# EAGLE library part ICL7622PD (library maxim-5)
OP AMP

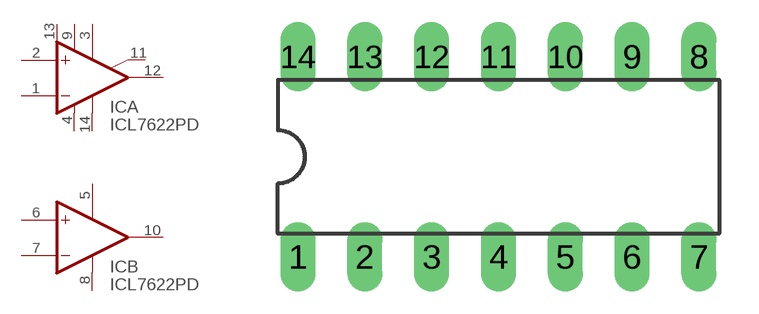
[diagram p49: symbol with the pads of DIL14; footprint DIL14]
Designator prefix IC; gates A=OPOFF+NC P=2V+V- B=OPOFF

## ICL7622PD  [DIL14]
1  A:-IN  in
2  A:+IN  in
3  A:OFF1  pas
4  P:V-  pwr
5  B:OFF1  pas
6  B:+IN  in
7  B:-IN  in
8  B:OFF2  pas
9  P:V+  pwr
10  B:OUT  out
11  A:NC  pas
12  A:OUT  out
13  P:V+  pwr
14  A:OFF2  pas

## Footprint DIL14 (pad centres in mm)
Dual In Line Package
drill 0.813 long: 1 -7.62,-3.81; 2 -5.08,-3.81; 3 -2.54,-3.81; 4 0,-3.81; 5 2.54,-3.81; 6 5.08,-3.81; 7 7.62,-3.81; 8 7.62,3.81; 9 5.08,3.81; 10 2.54,3.81; 11 0,3.81; 12 -2.54,3.81; 13 -5.08,3.81; 14 -7.62,3.81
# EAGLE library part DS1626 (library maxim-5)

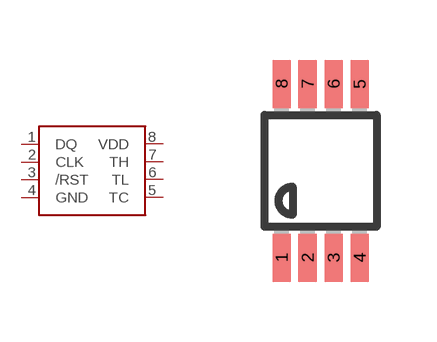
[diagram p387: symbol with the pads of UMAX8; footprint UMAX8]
Designator prefix IC

## DS1626  [UMAX8]
1  DQ
2  CLK
3  /RST
4  GND
5  TC
6  TL
7  TH
8  VDD

## Footprint UMAX8 (pad centres in mm)
micro MAX Package
smd 0.45 x 1.2: 1 -0.975,-2.175; 2 -0.325,-2.175; 3 0.325,-2.175; 4 0.975,-2.175; 5 0.975,2.175; 6 0.325,2.175; 7 -0.325,2.175; 8 -0.975,2.175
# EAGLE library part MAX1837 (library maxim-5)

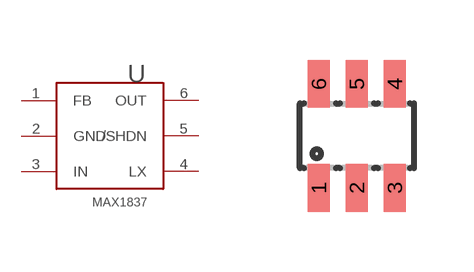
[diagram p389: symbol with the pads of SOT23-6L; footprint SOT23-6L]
Designator prefix -

## MAX1837SOT23  [SOT23-6L]
1  FB  in
2  GND  pwr
3  IN  in
4  LX  out
5  /SHDN  in
6  OUT  out

## Footprint SOT23-6L (pad centres in mm)
Small Outline Transistor
smd 0.55 x 1.2: 1 -0.95,-1.3; 2 0,-1.3; 3 0.95,-1.3; 4 0.95,1.3; 5 0,1.3; 6 -0.95,1.3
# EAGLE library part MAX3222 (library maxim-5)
RS232 TRANSCEIVER

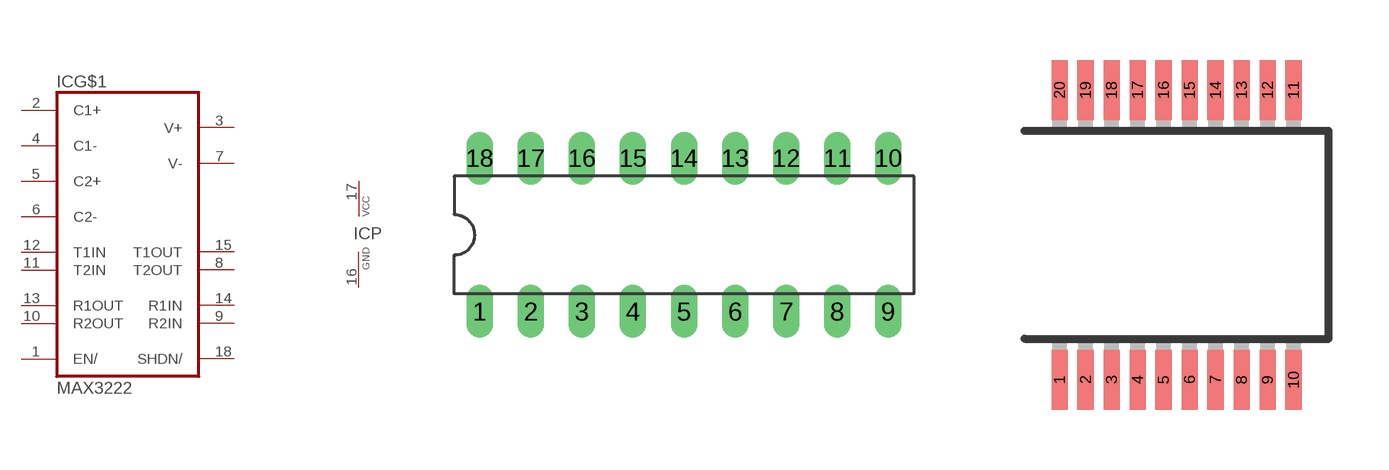
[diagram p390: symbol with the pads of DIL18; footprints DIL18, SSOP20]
Designator prefix IC; gates G$1=MAX3222 P=VCC-GND

## MAX3222CPN  [DIL18]
1  G$1:EN/  in
2  G$1:C1+  pas
3  G$1:V+  pas
4  G$1:C1-  pas
5  G$1:C2+  pas
6  G$1:C2-  pas
7  G$1:V-  pas
8  G$1:T2OUT  out
9  G$1:R2IN  in
10  G$1:R2OUT  out
11  G$1:T2IN  in
12  G$1:T1IN  in
13  G$1:R1OUT  out
14  G$1:R1IN  in
15  G$1:T1OUT  out
16  P:GND  pwr
17  P:VCC  pwr
18  G$1:SHDN/  in

## MAX3222CAP  [SSOP20]
1  G$1:EN/  in
2  G$1:C1+  pas
3  G$1:V+  pas
4  G$1:C1-  pas
5  G$1:C2+  pas
6  G$1:C2-  pas
7  G$1:V-  pas
8  G$1:T2OUT  out
9  G$1:R2IN  in
10  G$1:R2OUT  out
12  G$1:T2IN  in
13  G$1:T1IN  in
15  G$1:R1OUT  out
16  G$1:R1IN  in
17  G$1:T1OUT  out
18  P:GND  pwr
19  P:VCC  pwr
20  G$1:SHDN/  in

## MAX3222CUP  [TSSOP20]
Pads as for SSOP20

## MAX3222CWN  [SO18L]
Pads as for DIL18

## Footprint DIL18 (pad centres in mm)
Dual In Line Package
drill 0.813 long: 1 -10.16,-3.81; 2 -7.62,-3.81; 3 -5.08,-3.81; 4 -2.54,-3.81; 5 0,-3.81; 6 2.54,-3.81; 7 5.08,-3.81; 8 7.62,-3.81; 9 10.16,-3.81; 10 10.16,3.81; 11 7.62,3.81; 12 5.08,3.81; 13 2.54,3.81; 14 0,3.81; 15 -2.54,3.81; 16 -5.08,3.81; 17 -7.62,3.81; 18 -10.16,3.81

## Footprint SSOP20 (pad centres in mm)
Shrink Small Outline Package package type SS
smd 0.4 x 1.5: 1 -2.925,-3.625; 2 -2.275,-3.625; 3 -1.625,-3.625; 4 -0.975,-3.625; 5 -0.325,-3.625; 6 0.325,-3.625; 7 0.975,-3.625; 8 1.625,-3.625; 9 2.275,-3.625; 10 2.925,-3.625; 11 2.925,3.625; 12 2.275,3.625; 13 1.625,3.625; 14 0.975,3.625; 15 0.325,3.625; 16 -0.325,3.625; 17 -0.975,3.625; 18 -1.625,3.625; 19 -2.275,3.625; 20 -2.925,3.625

## Footprint TSSOP20 (pad centres in mm)
Thin Shrink Small Outline Plastic 20 MAX3223-MAX3243.pdf
smd 0.305 x 0.991: 1 -2.925,-2.918; 2 -2.275,-2.918; 3 -1.625,-2.918; 4 -0.975,-2.918; 5 -0.325,-2.918; 6 0.325,-2.918; 7 0.975,-2.918; 8 1.625,-2.918; 9 2.275,-2.918; 10 2.925,-2.918; 11 2.925,2.918; 12 2.275,2.918; 13 1.625,2.918; 14 0.975,2.918; 15 0.325,2.918; 16 -0.325,2.918; 17 -0.975,2.918; 18 -1.625,2.918; 19 -2.275,2.918; 20 -2.925,2.918

## Footprint SO18L (pad centres in mm)
Small Outline Package
smd 0.66 x 2.032: 1 -5.08,-4.902; 2 -3.81,-4.902; 3 -2.54,-4.902; 4 -1.27,-4.902; 5 0,-4.902; 6 1.27,-4.902; 7 2.54,-4.902; 8 3.81,-4.902; 9 5.08,-4.902; 10 5.08,4.902; 11 3.81,4.902; 12 2.54,4.902; 13 1.27,4.902; 14 0,4.902; 15 -1.27,4.902; 16 -2.54,4.902; 17 -3.81,4.902; 18 -5.08,4.902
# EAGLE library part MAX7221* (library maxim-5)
Serially Interfaced, 8-Digit LED Display Drivers

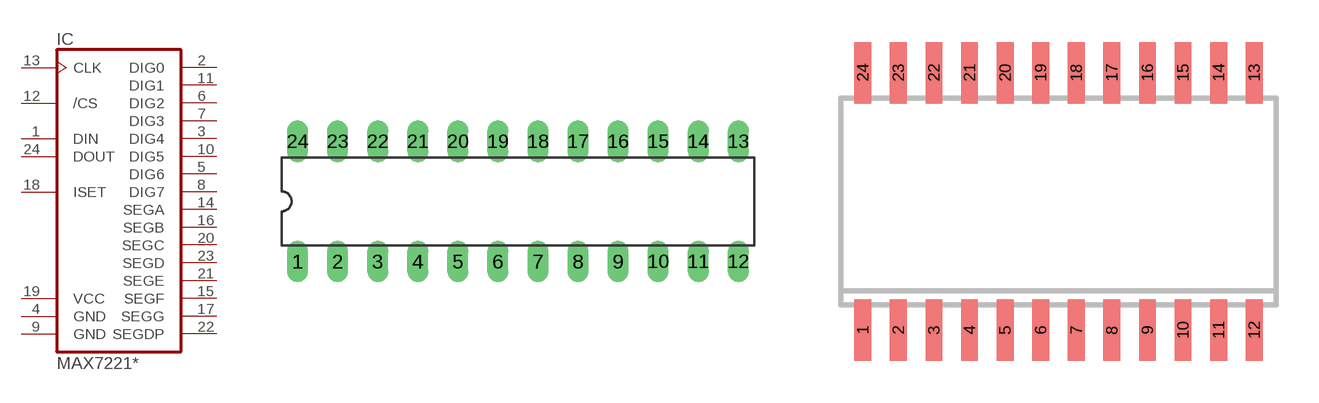
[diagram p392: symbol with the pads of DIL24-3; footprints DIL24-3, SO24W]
Designator prefix IC

## MAX7221CNG, MAX7221ENG  [DIL24-3]
1  DIN  in
2  DIG0  oc
3  DIG4  oc
4  GND  pwr
5  DIG6  oc
6  DIG2  oc
7  DIG3  oc
8  DIG7  oc
9  GND  pwr
10  DIG5  oc
11  DIG1  oc
12  /CS  in
13  CLK  in
14  SEGA  out
15  SEGF  out
16  SEGB  out
17  SEGG  out
18  ISET  in
19  VCC  pwr
20  SEGC  out
21  SEGE  out
22  SEGDP  out
23  SEGD  out
24  DOUT  out

## MAX7221CWG, MAX7221EWG  [SO24W]
Pads as for DIL24-3

## Footprint DIL24-3 (pad centres in mm)
Dual In Line Package 0.3 inch
drill 0.813 long: 1 -13.97,-3.81; 2 -11.43,-3.81; 3 -8.89,-3.81; 4 -6.35,-3.81; 5 -3.81,-3.81; 6 -1.27,-3.81; 7 1.27,-3.81; 8 3.81,-3.81; 9 6.35,-3.81; 10 8.89,-3.81; 11 11.43,-3.81; 12 13.97,-3.81; 13 13.97,3.81; 14 11.43,3.81; 15 8.89,3.81; 16 6.35,3.81; 17 3.81,3.81; 18 1.27,3.81; 19 -1.27,3.81; 20 -3.81,3.81; 21 -6.35,3.81; 22 -8.89,3.81; 23 -11.43,3.81; 24 -13.97,3.81

## Footprint SO24W (pad centres in mm)
SMALL OUTLINE INTEGRATED CIRCUIT wide body 7.5 mm/JEDEC MO-119AA
smd 0.6 x 2.2: 1 -6.985,-4.6; 2 -5.715,-4.6; 3 -4.445,-4.6; 4 -3.175,-4.6; 5 -1.905,-4.6; 6 -0.635,-4.6; 7 0.635,-4.6; 8 1.905,-4.6; 9 3.175,-4.6; 10 4.445,-4.6; 11 5.715,-4.6; 12 6.985,-4.6; 13 6.985,4.6; 14 5.715,4.6; 15 4.445,4.6; 16 3.175,4.6; 17 1.905,4.6; 18 0.635,4.6; 19 -0.635,4.6; 20 -1.905,4.6; 21 -3.175,4.6; 22 -4.445,4.6; 23 -5.715,4.6; 24 -6.985,4.6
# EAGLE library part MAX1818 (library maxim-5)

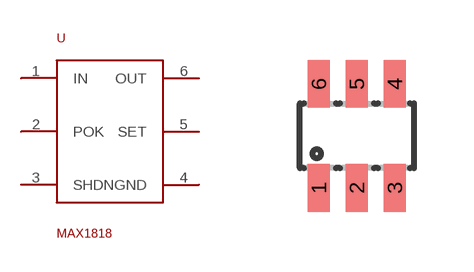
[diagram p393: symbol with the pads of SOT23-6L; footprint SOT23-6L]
Designator prefix -

## MAX1818  [SOT23-6L]
1  IN
2  POK
3  SHDN
4  GND
5  SET
6  OUT

## Footprint SOT23-6L (pad centres in mm)
Small Outline Transistor
smd 0.55 x 1.2: 1 -0.95,-1.3; 2 0,-1.3; 3 0.95,-1.3; 4 0.95,1.3; 5 0,1.3; 6 -0.95,1.3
